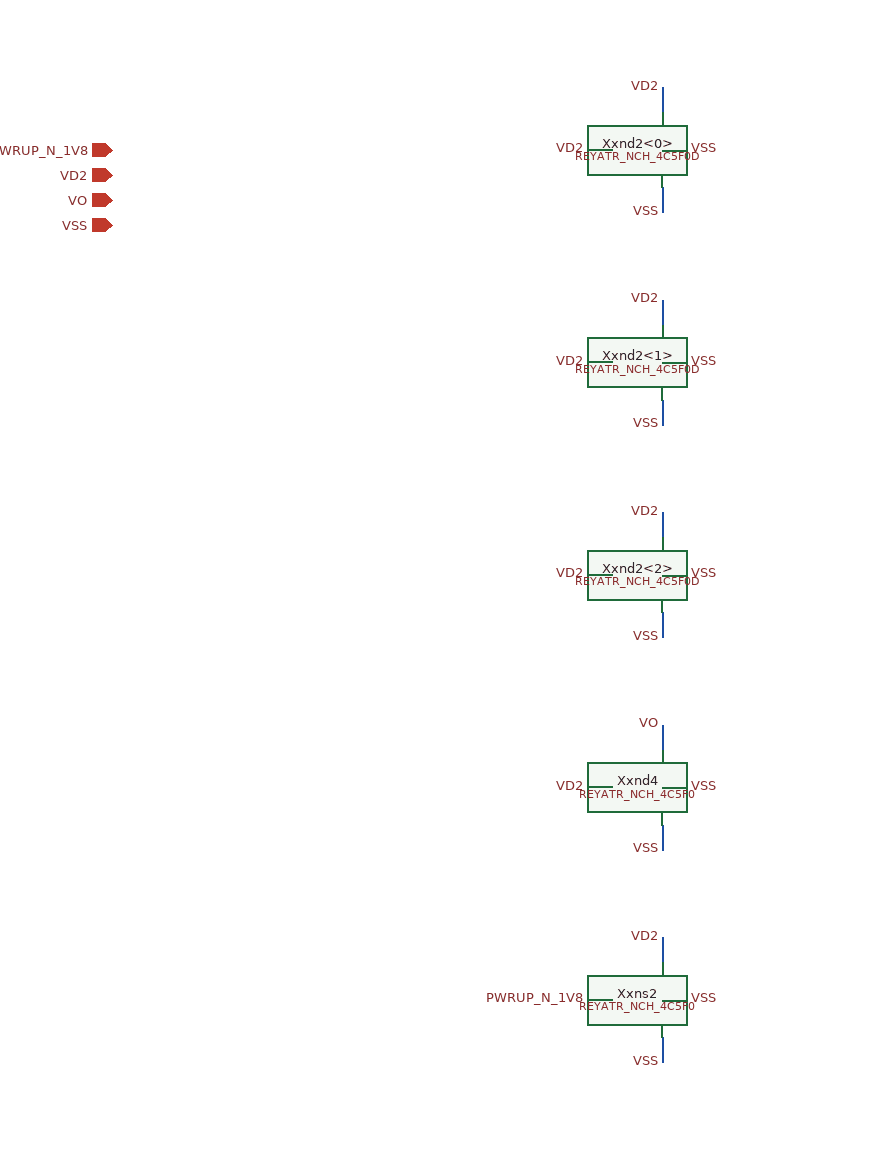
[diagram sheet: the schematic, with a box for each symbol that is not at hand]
v {xschem version=3.0.0 file_version=1.2 }
G {}
K {}
V {}
S {}
E {}
C {devices/iopin.sym} 0 0 0 0 {name=p0 lab=PWRUP_N_1V8}
C {devices/iopin.sym} 0 20 0 0 {name=p1 lab=VD2}
C {devices/iopin.sym} 0 40 0 0 {name=p2 lab=VO}
C {devices/iopin.sym} 0 60 0 0 {name=p3 lab=VSS}
C {LELO_TEMP_SKY130A/REYATR_NCH_4C5F0D.sym} 400 0 0 0 {name=Xxnd2<0>}
N 440.0 -50.0 440.0 -30.0 {lab=VD2}
C {devices/lab_pin.sym} 440.0 -50.0 3 0 {name=l0 sig_type=std_logic lab=VD2 }
N 380.0 0.0 400.0 0.0 {lab=VD2}
C {devices/lab_pin.sym} 380.0 0.0 0 0 {name=l1 sig_type=std_logic lab=VD2 }
N 440.0 50.0 440.0 30.0 {lab=VSS}
C {devices/lab_pin.sym} 440.0 50.0 1 0 {name=l2 sig_type=std_logic lab=VSS }
N 460.0 0.0 440.0 0.0 {lab=VSS}
C {devices/lab_pin.sym} 460.0 0.0 2 0 {name=l3 sig_type=std_logic lab=VSS }
C {LELO_TEMP_SKY130A/REYATR_NCH_4C5F0D.sym} 400 170.0 0 0 {name=Xxnd2<1>}
N 440.0 120.0 440.0 140.0 {lab=VD2}
C {devices/lab_pin.sym} 440.0 120.0 3 0 {name=l4 sig_type=std_logic lab=VD2 }
N 380.0 170.0 400.0 170.0 {lab=VD2}
C {devices/lab_pin.sym} 380.0 170.0 0 0 {name=l5 sig_type=std_logic lab=VD2 }
N 440.0 220.0 440.0 200.0 {lab=VSS}
C {devices/lab_pin.sym} 440.0 220.0 1 0 {name=l6 sig_type=std_logic lab=VSS }
N 460.0 170.0 440.0 170.0 {lab=VSS}
C {devices/lab_pin.sym} 460.0 170.0 2 0 {name=l7 sig_type=std_logic lab=VSS }
C {LELO_TEMP_SKY130A/REYATR_NCH_4C5F0D.sym} 400 340.0 0 0 {name=Xxnd2<2>}
N 440.0 290.0 440.0 310.0 {lab=VD2}
C {devices/lab_pin.sym} 440.0 290.0 3 0 {name=l8 sig_type=std_logic lab=VD2 }
N 380.0 340.0 400.0 340.0 {lab=VD2}
C {devices/lab_pin.sym} 380.0 340.0 0 0 {name=l9 sig_type=std_logic lab=VD2 }
N 440.0 390.0 440.0 370.0 {lab=VSS}
C {devices/lab_pin.sym} 440.0 390.0 1 0 {name=l10 sig_type=std_logic lab=VSS }
N 460.0 340.0 440.0 340.0 {lab=VSS}
C {devices/lab_pin.sym} 460.0 340.0 2 0 {name=l11 sig_type=std_logic lab=VSS }
C {LELO_TEMP_SKY130A/REYATR_NCH_4C5F0.sym} 400 510.0 0 0 {name=Xxnd4}
N 440.0 460.0 440.0 480.0 {lab=VO}
C {devices/lab_pin.sym} 440.0 460.0 3 0 {name=l12 sig_type=std_logic lab=VO }
N 380.0 510.0 400.0 510.0 {lab=VD2}
C {devices/lab_pin.sym} 380.0 510.0 0 0 {name=l13 sig_type=std_logic lab=VD2 }
N 440.0 560.0 440.0 540.0 {lab=VSS}
C {devices/lab_pin.sym} 440.0 560.0 1 0 {name=l14 sig_type=std_logic lab=VSS }
N 460.0 510.0 440.0 510.0 {lab=VSS}
C {devices/lab_pin.sym} 460.0 510.0 2 0 {name=l15 sig_type=std_logic lab=VSS }
C {LELO_TEMP_SKY130A/REYATR_NCH_4C5F0.sym} 400 680.0 0 0 {name=Xxns2}
N 440.0 630.0 440.0 650.0 {lab=VD2}
C {devices/lab_pin.sym} 440.0 630.0 3 0 {name=l16 sig_type=std_logic lab=VD2 }
N 380.0 680.0 400.0 680.0 {lab=PWRUP_N_1V8}
C {devices/lab_pin.sym} 380.0 680.0 0 0 {name=l17 sig_type=std_logic lab=PWRUP_N_1V8 }
N 440.0 730.0 440.0 710.0 {lab=VSS}
C {devices/lab_pin.sym} 440.0 730.0 1 0 {name=l18 sig_type=std_logic lab=VSS }
N 460.0 680.0 440.0 680.0 {lab=VSS}
C {devices/lab_pin.sym} 460.0 680.0 2 0 {name=l19 sig_type=std_logic lab=VSS }
